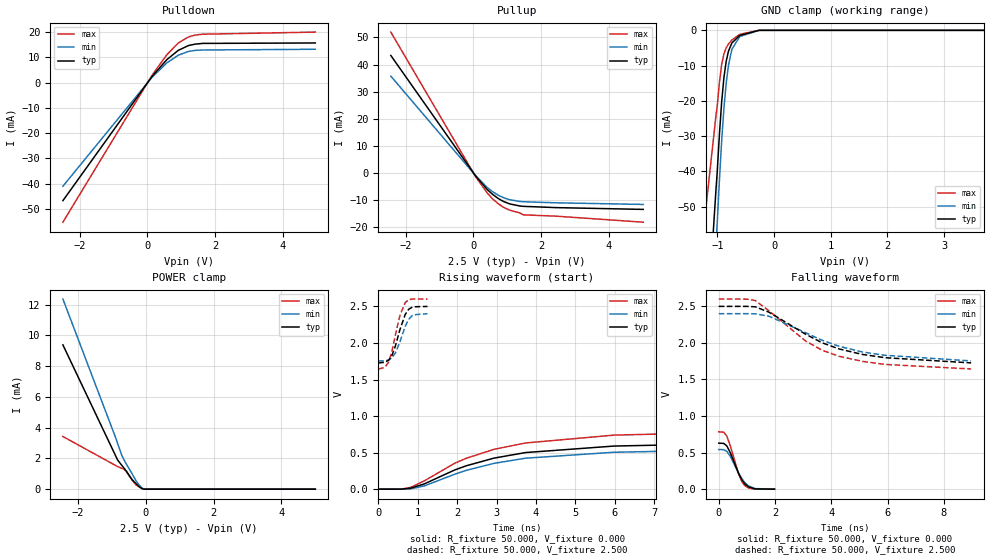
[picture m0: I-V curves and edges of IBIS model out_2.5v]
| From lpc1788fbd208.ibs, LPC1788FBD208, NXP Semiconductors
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[Model]   out_2.5v
Model_type Output
Vref=0.000E+00
Rref=1.000E+06
Cref=0.000E+00
Vmeas=1.250E+00
C_comp   8.160E-13   7.750E-13   8.570E-13
[Voltage Range]   2.500E+00   2.400E+00   2.600E+00
[POWER Clamp Reference]   2.500E+00   2.400E+00   2.600E+00
[GND Clamp Reference]   0.000E+00   0.000E+00   0.000E+00
[Pullup Reference]   2.500E+00   2.400E+00   2.600E+00
[Pulldown Reference]   0.000E+00   0.000E+00   0.000E+00
[Temperature Range]   25   85   -40
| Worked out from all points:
|   slope of the pulldown table from 0 to 0.375 V, typ, clamps not added: 60.1 ohm
|   slope of the pullup table from 0 to 0.375 V, typ, clamps not added: 66.3 ohm
|   GND clamp passes 1 mA (typ) near -0.56 V on its own axis
|   POWER clamp passes 1 mA (typ) near -0.52 V on its own axis
|   rising waveform, R_fixture 50.000, V_fixture 0.000: 20-80 % time 2.39ns typ, 2.4ns min, 2.39ns max; typ from 0 V to 0.629 V
|   falling waveform, R_fixture 50.000, V_fixture 0.000: 20-80 % time 421ps typ, 454ps min, 375ps max; typ from 0.629 V to 0 V
|   rising waveform, R_fixture 50.000, V_fixture 2.500: 20-80 % time 260ps typ, 267ps min, 245ps max; typ from 1.73 V to 2.5 V
|   falling waveform, R_fixture 50.000, V_fixture 2.500: 20-80 % time 2.52ns typ, 2.66ns min, 2.25ns max; typ from 2.5 V to 1.73 V
[GND Clamp]
-2.5V     -415.3mA   -495.5mA   -241.3mA
-1.024V   -44.7mA    -60.18mA   -23.89mA
-1.004V   -40.2mA    -54.65mA   -21.5mA
-964.1mV  -29.24mA   -42.23mA   -14.61mA
-924.2mV  -20.02mA   -31.02mA   -9.581mA
-884.3mV  -13.21mA   -21.82mA   -6.601mA
-844.4mV  -8.671mA   -14.8mA    -4.92mA
-804.5mV  -5.864mA   -9.818mA   -3.864mA
-744.7mV  -3.573mA   -5.336mA   -2.735mA
-605.1mV  -1.438mA   -1.745mA   -1.126mA
-266mV    0A         0A         0A
5V        0A         0A         0A
[Power Clamp]
-2.44V    9.388mA    12.37mA    3.427mA
-864.3mV  2.069mA    3.227mA    1.515mA
-824.4mV  1.888mA    2.953mA    1.468mA
-704.7mV  1.555mA    2.207mA    1.357mA
-644.9mV  1.391mA    1.935mA    1.317mA
-565.1mV  1.161mA    1.609mA    1.121mA
-405.5mV  639.5uA    1.023mA    599.2uA
-285.8mV  358.5uA    551.8uA    272.7uA
-206mV    179.2uA    299.1uA    176uA
-106.3mV  38.2uA     67.27uA    36.76uA
-46.45mV  0A         0A         0A
5V        0A         0A         0A
[Pullup]
-2.44V    43.36mA    35.74mA    51.99mA
73.23mV   -1.212mA   -1.083mA   -1.512mA
412.3mV   -6.134mA   -5.372mA   -7.408mA
571.9mV   -7.907mA   -6.919mA   -9.588mA
731.5mV   -9.384mA   -8.178mA   -11.31mA
891mV     -10.51mA   -9.115mA   -12.66mA
1.071V    -11.38mA   -9.854mA   -13.7mA
1.37V     -12.17mA   -10.49mA   -14.71mA
1.47V     -12.3mA    -10.6mA    -15.43mA
2.447V    -12.77mA   -11mA      -15.93mA
5.02V     -13.43mA   -11.6mA    -18.15mA
[Pulldown]
-2.5V     -46.78mA   -41.06mA   -55.31mA
133mV     2.372mA    2.061mA    2.84mA
571.8mV   9.068mA    7.781mA    11mA
910.9mV   12.75mA    10.83mA    15.67mA
1.21V     14.64mA    12.31mA    18.05mA
1.409V    15.21mA    12.73mA    18.81mA
1.629V    15.5mA     12.89mA    19.14mA
4.96V     15.67mA    13.17mA    19.98mA
[Rising Waveform]
R_fixture = 50.000
V_fixture = 0.000
V_fixture_min = 0.000
V_fixture_max = 0.000
|  time   V(typ)   V(min)   V(max)
0s        0V         0V         0V
589.4ps   280.9uV    -130uV     680.1uV
819.1ps   13.11mV    3.684mV    24.01mV
1.169ns   71.91mV    44.1mV     113.2mV
1.938ns   262mV      203.9mV    353.7mV
2.228ns   319mV      256.6mV    421.4mV
2.937ns   424.8mV    353.1mV    545.1mV
3.736ns   500.7mV    423.6mV    631.9mV
5.984ns   589.9mV    505.2mV    739.5mV
9.53ns    629.3mV    541.7mV    784.8mV
[Falling Waveform]
R_fixture = 50.000
V_fixture = 0.000
V_fixture_min = 0.000
V_fixture_max = 0.000
|  time   V(typ)   V(min)   V(max)
0s        629.3mV    541.7mV    784.8mV
179.1ps   625.7mV    540.3mV    778.6mV
288.6ps   591.3mV    517.2mV    725.2mV
410ps     499.6mV    450.4mV    593.4mV
706.5ps   215.8mV    216.6mV    208.4mV
815.9ps   132.4mV    146.7mV    107.5mV
915.4ps   76.07mV    94.62mV    51.88mV
1.05ns    32.54mV    47.11mV    17.48mV
1.284ns   3.901mV    7.986mV    310.5uV
1.98ns    0V         0V         0V
[Rising Waveform]
R_fixture = 50.000
V_fixture = 2.500
V_fixture_min = 2.400
V_fixture_max = 2.600
|  time   V(typ)   V(min)   V(max)
0s        1.727V     1.754V     1.644V
168.7ps   1.735V     1.755V     1.665V
267.9ps   1.766V     1.768V     1.742V
347.2ps   1.827V     1.796V     1.882V
436.5ps   1.959V     1.863V     2.112V
550ps     2.181V     2.015V     2.375V
684.6ps   2.389V     2.227V     2.552V
773.9ps   2.462V     2.324V     2.594V
880ps     2.495V     2.385V     2.601V
1.25ns    2.5V       2.4V       2.6V
[Falling Waveform]
R_fixture = 50.000
V_fixture = 2.500
V_fixture_min = 2.400
V_fixture_max = 2.600
|  time   V(typ)   V(min)   V(max)
0s        2.5V       2.4V       2.6V
998.9ps   2.5V       2.4V       2.599V
1.299ns   2.494V     2.398V     2.58V
1.788ns   2.42V      2.365V     2.438V
3.087ns   2.119V     2.14V      2.026V
3.676ns   2.002V     2.036V     1.9V
4.275ns   1.918V     1.954V     1.817V
5.104ns   1.843V     1.876V     1.748V
5.913ns   1.798V     1.831V     1.706V
8.97ns    1.727V     1.754V     1.644V
[Ramp]
dV/dt_r   3.7967E-01/2.3879E-09   3.2490E-01/2.3920E-09   4.7355E-01/2.3872E-09
dV/dt_f   4.6402E-01/2.5227E-09   3.8788E-01/2.6605E-09   5.7347E-01/2.2506E-09
R_load = 50
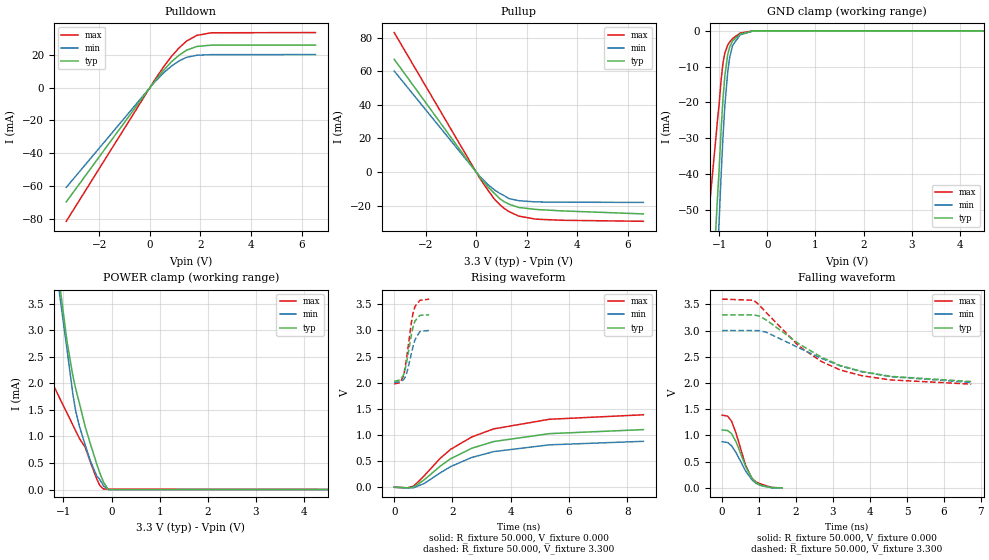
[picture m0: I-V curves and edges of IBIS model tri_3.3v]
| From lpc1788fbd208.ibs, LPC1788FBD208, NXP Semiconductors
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[Model]   tri_3.3v
Model_type 3-state
Vref=0.000E+00
Rref=1.000E+06
Cref=0.000E+00
Vmeas=1.650E+00
C_comp   6.490E-13   6.170E-13   6.810E-13
[Voltage Range]   3.300E+00   3.000E+00   3.600E+00
[POWER Clamp Reference]   3.300E+00   3.000E+00   3.600E+00
[GND Clamp Reference]   0.000E+00   0.000E+00   0.000E+00
[Pullup Reference]   3.300E+00   3.000E+00   3.600E+00
[Pulldown Reference]   0.000E+00   0.000E+00   0.000E+00
[Temperature Range]   25   85   -40
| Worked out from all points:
|   slope of the pulldown table from 0 to 0.495 V, typ, clamps not added: 51.4 ohm
|   slope of the pullup table from 0 to 0.495 V, typ, clamps not added: 53.6 ohm
|   GND clamp passes 1 mA (typ) near -0.58 V on its own axis
|   POWER clamp passes 1 mA (typ) near -0.49 V on its own axis
|   rising waveform, R_fixture 50.000, V_fixture 0.000: 20-80 % time 2.29ns typ, 2.31ns min, 2.24ns max; typ from 0 V to 1.1 V
|   falling waveform, R_fixture 50.000, V_fixture 0.000: 20-80 % time 396ps typ, 429ps min, 378ps max; typ from 1.1 V to 0 V
|   rising waveform, R_fixture 50.000, V_fixture 3.300: 20-80 % time 251ps typ, 258ps min, 246ps max; typ from 2.03 V to 3.3 V
|   falling waveform, R_fixture 50.000, V_fixture 3.300: 20-80 % time 1.94ns typ, 2.12ns min, 1.72ns max; typ from 3.3 V to 2.03 V
[GND Clamp]
-3.3V     -606.2mA   -727.4mA   -351.7mA
-1.025V   -43.68mA   -59.25mA   -23.29mA
-1.005V   -39.24mA   -53.76mA   -20.92mA
-964.7mV  -28.46mA   -41.34mA   -14.2mA
-924.8mV  -19.34mA   -30.19mA   -9.228mA
-884.9mV  -12.66mA   -21.11mA   -6.241mA
-825mV    -6.69mA    -11.58mA   -4.019mA
-785.1mV  -4.574mA   -7.59mA    -3.144mA
-725.2mV  -2.861mA   -4.134mA   -2.185mA
-565.5mV  -895.1uA   -1.139mA   -618.2uA
-286.1mV  0A         0A         0A
6.6V      0A         0A         0A
[Power Clamp]
-3.24V    19.03mA    18.2mA     5.713mA
-924.7mV  2.781mA    2.629mA    1.437mA
-805mV    2.145mA    1.804mA    1.216mA
-745.1mV  1.897mA    1.475mA    1.105mA
-665.3mV  1.616mA    1.183mA    959.4uA
-545.5mV  1.176mA    832.6uA    791.6uA
-445.7mV  877.7uA    553.9uA    532.7uA
-306mV    477.3uA    253.1uA    198.3uA
-246.1mV  317uA      192.2uA    82.37uA
-166.3mV  139.1uA    70.82uA    10.73uA
-66.46mV  0A         0A         10.73uA
6.6V      0A         0A         0A
[Pullup]
-3.24V    67.13mA    60.13mA    83.01mA
153.1mV   -3.115mA   -2.633mA   -3.8mA
472.4mV   -8.877mA   -7.516mA   -10.8mA
731.9mV   -12.79mA   -10.65mA   -16.25mA
951.5mV   -16mA      -12.79mA   -19.57mA
1.111V    -17.61mA   -14.02mA   -21.61mA
1.291V    -19.04mA   -15.72mA   -23.43mA
1.69V     -21.07mA   -17.04mA   -26.21mA
2.369V    -22.24mA   -17.77mA   -28.02mA
3.386V    -23.09mA   -17.92mA   -28.68mA
6.62V     -24.89mA   -18.05mA   -29.29mA
[Pulldown]
-3.3V     -69.51mA   -60.72mA   -81.36mA
173mV     3.544mA    3.051mA    4.203mA
572.2mV   11.04mA    9.362mA    13.26mA
851.6mV   15.69mA    13.04mA    18.9mA
1.151V    19.67mA    16.22mA    24.12mA
1.45V     22.74mA    18.41mA    28.3mA
1.85V     25.01mA    19.67mA    31.76mA
2.428V    25.82mA    20.06mA    33.34mA
6.54V     25.88mA    20.09mA    33.48mA
[Rising Waveform]
R_fixture = 50.000
V_fixture = 0.000
V_fixture_min = 0.000
V_fixture_max = 0.000
|  time   V(typ)   V(min)   V(max)
0s        0V         0V         -108.1uV
459.5ps   -10.85mV   -11.41mV   -10.61mV
669.2ps   7.036mV    -8.375mV   22.84mV
1.029ns   141.7mV    72.83mV    219.2mV
1.588ns   408mV      278.2mV    559mV
1.938ns   546.5mV    395.9mV    726.4mV
2.657ns   745.7mV    568.7mV    961.5mV
3.406ns   873.9mV    681.6mV    1.116V
5.324ns   1.026V     811.7mV    1.301V
8.55ns    1.103V     879.4mV    1.387V
[Falling Waveform]
R_fixture = 50.000
V_fixture = 0.000
V_fixture_min = 0.000
V_fixture_max = 0.000
|  time   V(typ)   V(min)   V(max)
0s        1.103V     879.4mV    1.387V
149.1ps   1.094V     865.2mV    1.369V
258.4ps   1.032V     802.1mV    1.269V
380ps     872.7mV    666.2mV    1.035V
636.1ps   412.4mV    322.5mV    427.7mV
805.1ps   181.7mV    154.5mV    181.4mV
920ps     95.74mV    84.37mV    109.7mV
1.07ns    45.07mV    37.54mV    67.8mV
1.34ns    4.345mV    2.922mV    7.915mV
1.62ns    0V         0V         -108.1uV
[Rising Waveform]
R_fixture = 50.000
V_fixture = 3.300
V_fixture_min = 3.000
V_fixture_max = 3.600
|  time   V(typ)   V(min)   V(max)
0s        2.028V     2.01V      1.979V
208.3ps   2.052V     2.017V     2.002V
317.4ps   2.146V     2.056V     2.13V
376.9ps   2.258V     2.108V     2.287V
440ps     2.436V     2.201V     2.528V
595.1ps   2.939V     2.572V     3.173V
654.6ps   3.083V     2.712V     3.348V
714.1ps   3.183V     2.824V     3.461V
882.7ps   3.29V      2.981V     3.577V
1.2ns     3.3V       3V         3.6V
[Falling Waveform]
R_fixture = 50.000
V_fixture = 3.300
V_fixture_min = 3.000
V_fixture_max = 3.600
|  time   V(typ)   V(min)   V(max)
0s        3.3V       3V         3.6V
848.7ps   3.299V     3V         3.579V
998.5ps   3.279V     2.998V     3.493V
1.19ns    3.204V     2.971V     3.346V
2.077ns   2.747V     2.67V      2.703V
2.686ns   2.493V     2.47V      2.41V
3.195ns   2.334V     2.326V     2.248V
3.774ns   2.221V     2.215V     2.14V
4.553ns   2.127V     2.121V     2.059V
6.74ns    2.028V     2.01V      1.979V
[Ramp]
dV/dt_r   6.6398E-01/2.2826E-09   5.2663E-01/2.2984E-09   8.3162E-01/2.2450E-09
dV/dt_f   7.6318E-01/1.9388E-09   5.9404E-01/2.1204E-09   9.7259E-01/1.7147E-09
R_load = 50
